# Minimal tech LEF — default routing widths (um), sky130-class (illustrative).
# Optional: supplies edge-to-edge gaps for coupling. Same shape as counter.lef.
VERSION 5.8 ;

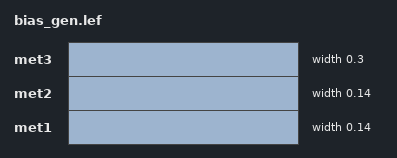
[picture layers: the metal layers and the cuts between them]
LAYER met1
   TYPE ROUTING ;
   WIDTH 0.14 ;
END met1

LAYER met2
   TYPE ROUTING ;
   WIDTH 0.14 ;
END met2

LAYER met3
   TYPE ROUTING ;
   WIDTH 0.30 ;
END met3

END LIBRARY
